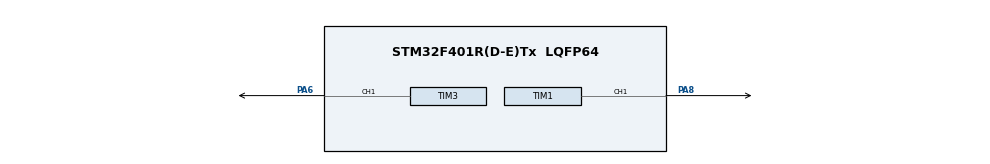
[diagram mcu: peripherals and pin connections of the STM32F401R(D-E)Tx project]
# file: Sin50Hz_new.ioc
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Dma.Request0=TIM1_CH1
Dma.Request1=TIM3_CH1/TRIG
Dma.TIM1_CH1.0.Direction=DMA_MEMORY_TO_PERIPH
Dma.TIM1_CH1.0.FIFOMode=DMA_FIFOMODE_DISABLE
Dma.TIM1_CH1.0.Instance=DMA2_Stream1
Dma.TIM1_CH1.0.MemDataAlignment=DMA_MDATAALIGN_HALFWORD
Dma.TIM1_CH1.0.MemInc=DMA_MINC_ENABLE
Dma.TIM1_CH1.0.Mode=DMA_CIRCULAR
Dma.TIM1_CH1.0.PeriphDataAlignment=DMA_PDATAALIGN_HALFWORD
Dma.TIM1_CH1.0.PeriphInc=DMA_PINC_DISABLE
Dma.TIM1_CH1.0.Priority=DMA_PRIORITY_LOW
Dma.TIM3_CH1/TRIG.1.Direction=DMA_MEMORY_TO_PERIPH
Dma.TIM3_CH1/TRIG.1.FIFOMode=DMA_FIFOMODE_DISABLE
Dma.TIM3_CH1/TRIG.1.Instance=DMA1_Stream4
Dma.TIM3_CH1/TRIG.1.MemDataAlignment=DMA_MDATAALIGN_HALFWORD
Dma.TIM3_CH1/TRIG.1.MemInc=DMA_MINC_ENABLE
Dma.TIM3_CH1/TRIG.1.Mode=DMA_CIRCULAR
Dma.TIM3_CH1/TRIG.1.PeriphDataAlignment=DMA_PDATAALIGN_HALFWORD
Dma.TIM3_CH1/TRIG.1.PeriphInc=DMA_PINC_DISABLE
Dma.TIM3_CH1/TRIG.1.Priority=DMA_PRIORITY_LOW
Mcu.Family=STM32F4
Mcu.Name=STM32F401R(D-E)Tx
Mcu.Package=LQFP64
NVIC.DMA1_Stream4_IRQn=true\:0\:0\:false\:false\:true\:false\:true
NVIC.DMA2_Stream1_IRQn=true\:0\:0\:false\:false\:true\:false\:true
NVIC.PriorityGroup=NVIC_PRIORITYGROUP_4
PA6.Signal=S_TIM3_CH1
PA8.Signal=S_TIM1_CH1
ProjectManager.HeapSize=0x200
ProjectManager.StackSize=0x400
ProjectManager.TargetToolchain=STM32CubeIDE
RCC.AHBFreq_Value=16000000
RCC.APB1Freq_Value=16000000
RCC.APB2Freq_Value=16000000
RCC.CortexFreq_Value=16000000
RCC.HSE_VALUE=25000000
RCC.HSI_VALUE=16000000
RCC.LSE_VALUE=32768
RCC.SYSCLKFreq_VALUE=16000000
RCC.VCOOutputFreq_Value=192000000
SH.S_TIM1_CH1.0=TIM1_CH1,PWM Generation1 CH1
SH.S_TIM3_CH1.0=TIM3_CH1,PWM Generation1 CH1
TIM1.Channel-PWM\ Generation1\ CH1=TIM_CHANNEL_1
TIM1.ClockDivision=TIM_CLOCKDIVISION_DIV4
TIM1.Period=199
TIM1.Prescaler=23
TIM3.Channel-PWM\ Generation1\ CH1=TIM_CHANNEL_1
TIM3.ClockDivision=TIM_CLOCKDIVISION_DIV4
TIM3.Period=199
TIM3.Prescaler=23
board=custom

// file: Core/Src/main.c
/* USER CODE BEGIN Header */
/**
  ******************************************************************************
  * @file           : main.c
  * @brief          : Main program body
  ******************************************************************************
  * @attention
  *
  * Copyright (c) 2021 STMicroelectronics.
  * All rights reserved.
  *
  * This software is licensed under terms that can be found in the LICENSE file
  * in the root directory of this software component.
  * If no LICENSE file comes with this software, it is provided AS-IS.
  *
  ******************************************************************************
  */
/* USER CODE END Header */
#include "main.h"

/* USER CODE BEGIN Includes */
#define PI 3.14159
#define ASR 1.8 //360 / 200 = 1.8
/* USER CODE END Includes */

TIM_HandleTypeDef htim1;
TIM_HandleTypeDef htim3;
DMA_HandleTypeDef hdma_tim1_ch1;
DMA_HandleTypeDef hdma_tim3_ch1_trig;

void SystemClock_Config(void);
static void MX_GPIO_Init(void);
static void MX_DMA_Init(void);
static void MX_TIM1_Init(void);
static void MX_TIM3_Init(void);

int main(void)
{
  /* USER CODE BEGIN 1 */
	uint16_t IV[200];
	uint16_t IV2[200];
		float angle;
  /* USER CODE END 1 */

  /* MCU Configuration--------------------------------------------------------*/

  /* Reset of all peripherals, Initializes the Flash interface and the Systick. */
  HAL_Init();

  /* Configure the system clock */
  SystemClock_Config();

  /* Initialize all configured peripherals */
  MX_GPIO_Init();
  MX_DMA_Init();
  MX_TIM1_Init();
  MX_TIM3_Init();
  /* USER CODE BEGIN 2 */
  for (uint8_t i = 0; i < 200; i++) {
  		angle = ASR * (float) i;
  		IV[i] = (uint16_t) rint(100 + 99 * sinf(angle * (PI / 180)));
  	}

  for (uint8_t i = 0; i < 200; i++) {
  		angle = ASR * (float) (i+50);
  		IV2[i] = (uint16_t) rint(100 + 99 * sinf(angle * (PI / 180)));
  	}

    HAL_TIM_PWM_Start_DMA(&htim3, TIM_CHANNEL_1, (uint32_t *)IV, 200);

    HAL_TIM_PWM_Start_DMA(&htim1, TIM_CHANNEL_1, (uint32_t *)IV2, 200);
  /* USER CODE END 2 */

  /* Infinite loop */
  while (1)
  {

  }
}

void SystemClock_Config(void)
{
	RCC_OscInitTypeDef RCC_OscInitStruct = {0};
	  RCC_ClkInitTypeDef RCC_ClkInitStruct = {0};

	  /** Configure the main internal regulator output voltage
	  */
	  __HAL_RCC_PWR_CLK_ENABLE();
	  __HAL_PWR_VOLTAGESCALING_CONFIG(PWR_REGULATOR_VOLTAGE_SCALE2);
	  /** Initializes the RCC Oscillators according to the specified parameters
	  * in the RCC_OscInitTypeDef structure.
	  */
	  RCC_OscInitStruct.OscillatorType = RCC_OSCILLATORTYPE_HSI;
	  RCC_OscInitStruct.HSIState = RCC_HSI_ON;
	  RCC_OscInitStruct.HSICalibrationValue = RCC_HSICALIBRATION_DEFAULT;
	  RCC_OscInitStruct.PLL.PLLState = RCC_PLL_ON;
	  RCC_OscInitStruct.PLL.PLLSource = RCC_PLLSOURCE_HSI;
	  RCC_OscInitStruct.PLL.PLLM = 8;
	  RCC_OscInitStruct.PLL.PLLN = 96;
	  RCC_OscInitStruct.PLL.PLLP = RCC_PLLP_DIV4;
	  RCC_OscInitStruct.PLL.PLLQ = 4;
	  if (HAL_RCC_OscConfig(&RCC_OscInitStruct) != HAL_OK)
	  {
	    Error_Handler();
	  }
	  /** Initializes the CPU, AHB and APB buses clocks
	  */
	  RCC_ClkInitStruct.ClockType = RCC_CLOCKTYPE_HCLK|RCC_CLOCKTYPE_SYSCLK
	                              |RCC_CLOCKTYPE_PCLK1|RCC_CLOCKTYPE_PCLK2;
	  RCC_ClkInitStruct.SYSCLKSource = RCC_SYSCLKSOURCE_PLLCLK;
	  RCC_ClkInitStruct.AHBCLKDivider = RCC_SYSCLK_DIV1;
	  RCC_ClkInitStruct.APB1CLKDivider = RCC_HCLK_DIV2;
	  RCC_ClkInitStruct.APB2CLKDivider = RCC_HCLK_DIV1;

	  if (HAL_RCC_ClockConfig(&RCC_ClkInitStruct, FLASH_LATENCY_1) != HAL_OK)
	  {
	    Error_Handler();
	  }
}

static void MX_TIM1_Init(void)
{

  TIM_MasterConfigTypeDef sMasterConfig = {0};
  TIM_OC_InitTypeDef sConfigOC = {0};
  TIM_BreakDeadTimeConfigTypeDef sBreakDeadTimeConfig = {0};

  htim1.Instance = TIM1;
  htim1.Init.Prescaler = 23;
  htim1.Init.CounterMode = TIM_COUNTERMODE_UP;
  htim1.Init.Period = 199;
  htim1.Init.ClockDivision = TIM_CLOCKDIVISION_DIV4;
  htim1.Init.RepetitionCounter = 0;
  htim1.Init.AutoReloadPreload = TIM_AUTORELOAD_PRELOAD_DISABLE;
  if (HAL_TIM_PWM_Init(&htim1) != HAL_OK)
  {
    Error_Handler();
  }
  sMasterConfig.MasterOutputTrigger = TIM_TRGO_RESET;
  sMasterConfig.MasterSlaveMode = TIM_MASTERSLAVEMODE_DISABLE;
  if (HAL_TIMEx_MasterConfigSynchronization(&htim1, &sMasterConfig) != HAL_OK)
  {
    Error_Handler();
  }
  sConfigOC.OCMode = TIM_OCMODE_PWM1;
  sConfigOC.Pulse = 0;
  sConfigOC.OCPolarity = TIM_OCPOLARITY_HIGH;
  sConfigOC.OCNPolarity = TIM_OCNPOLARITY_HIGH;
  sConfigOC.OCFastMode = TIM_OCFAST_DISABLE;
  sConfigOC.OCIdleState = TIM_OCIDLESTATE_RESET;
  sConfigOC.OCNIdleState = TIM_OCNIDLESTATE_RESET;
  if (HAL_TIM_PWM_ConfigChannel(&htim1, &sConfigOC, TIM_CHANNEL_1) != HAL_OK)
  {
    Error_Handler();
  }
  sBreakDeadTimeConfig.OffStateRunMode = TIM_OSSR_DISABLE;
  sBreakDeadTimeConfig.OffStateIDLEMode = TIM_OSSI_DISABLE;
  sBreakDeadTimeConfig.LockLevel = TIM_LOCKLEVEL_OFF;
  sBreakDeadTimeConfig.DeadTime = 0;
  sBreakDeadTimeConfig.BreakState = TIM_BREAK_DISABLE;
  sBreakDeadTimeConfig.BreakPolarity = TIM_BREAKPOLARITY_HIGH;
  sBreakDeadTimeConfig.AutomaticOutput = TIM_AUTOMATICOUTPUT_DISABLE;
  if (HAL_TIMEx_ConfigBreakDeadTime(&htim1, &sBreakDeadTimeConfig) != HAL_OK)
  {
    Error_Handler();
  }
  HAL_TIM_MspPostInit(&htim1);

}

static void MX_TIM3_Init(void)
{

  TIM_MasterConfigTypeDef sMasterConfig = {0};
  TIM_OC_InitTypeDef sConfigOC = {0};

  htim3.Instance = TIM3;
  htim3.Init.Prescaler = 23;
  htim3.Init.CounterMode = TIM_COUNTERMODE_UP;
  htim3.Init.Period = 199;
  htim3.Init.ClockDivision = TIM_CLOCKDIVISION_DIV4;
  htim3.Init.AutoReloadPreload = TIM_AUTORELOAD_PRELOAD_DISABLE;
  if (HAL_TIM_PWM_Init(&htim3) != HAL_OK)
  {
    Error_Handler();
  }
  sMasterConfig.MasterOutputTrigger = TIM_TRGO_RESET;
  sMasterConfig.MasterSlaveMode = TIM_MASTERSLAVEMODE_DISABLE;
  if (HAL_TIMEx_MasterConfigSynchronization(&htim3, &sMasterConfig) != HAL_OK)
  {
    Error_Handler();
  }
  sConfigOC.OCMode = TIM_OCMODE_PWM1;
  sConfigOC.Pulse = 0;
  sConfigOC.OCPolarity = TIM_OCPOLARITY_HIGH;
  sConfigOC.OCFastMode = TIM_OCFAST_DISABLE;
  if (HAL_TIM_PWM_ConfigChannel(&htim3, &sConfigOC, TIM_CHANNEL_1) != HAL_OK)
  {
    Error_Handler();
  }
  HAL_TIM_MspPostInit(&htim3);

}

static void MX_DMA_Init(void)
{

  /* DMA controller clock enable */
  __HAL_RCC_DMA2_CLK_ENABLE();
  __HAL_RCC_DMA1_CLK_ENABLE();

  /* DMA interrupt init */
  /* DMA1_Stream4_IRQn interrupt configuration */
  HAL_NVIC_SetPriority(DMA1_Stream4_IRQn, 0, 0);
  HAL_NVIC_EnableIRQ(DMA1_Stream4_IRQn);
  /* DMA2_Stream1_IRQn interrupt configuration */
  HAL_NVIC_SetPriority(DMA2_Stream1_IRQn, 0, 0);
  HAL_NVIC_EnableIRQ(DMA2_Stream1_IRQn);

}

static void MX_GPIO_Init(void)
{

  /* GPIO Ports Clock Enable */
  __HAL_RCC_GPIOA_CLK_ENABLE();

}

void Error_Handler(void)
{
  __disable_irq();
  while (1)
  {
  }
}
